VERSION 5.8 ;
BUSBITCHARS "[]" ;
DIVIDERCHAR "/" ;
UNITS
    DATABASE MICRONS 1000 ;
END UNITS

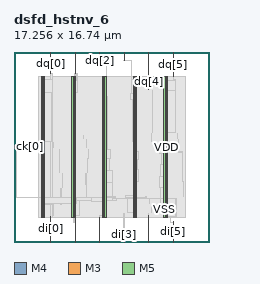
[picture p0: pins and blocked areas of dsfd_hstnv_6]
MACRO dsfd_hstnv_6
  FOREIGN dsfd_hstnv_6 0 0 ;
  CLASS BLOCK ;
  SIZE 17.256 BY 16.74 ;
  PIN ck[0]
    DIRECTION INPUT ;
    USE SIGNAL ;
    PORT
      LAYER M4 ;
        RECT  0 8.4 0.192 8.424 ;
    END
    PORT
      LAYER M4 ;
        RECT  0.156 8.4 0.275 8.424 ;
    END
  END ck[0]
  PIN di[0]
    DIRECTION INPUT ;
    USE SIGNAL ;
    PORT
      LAYER M3 ;
        RECT  3.24 0 3.258 0.144 ;
    END
    PORT
      LAYER M3 ;
        RECT  3.24 0.108 3.258 2.255 ;
    END
  END di[0]
  PIN di[1]
    DIRECTION INPUT ;
    USE SIGNAL ;
    PORT
      LAYER M5 ;
        RECT  5.376 0 5.4 0.192 ;
    END
    PORT
      LAYER M5 ;
        RECT  5.376 0.144 5.4 2.137 ;
    END
  END di[1]
  PIN di[2]
    DIRECTION INPUT ;
    USE SIGNAL ;
    PORT
      LAYER M3 ;
        RECT  7.524 0 7.542 0.144 ;
    END
    PORT
      LAYER M3 ;
        RECT  7.524 0.108 7.542 2.143 ;
    END
  END di[2]
  PIN di[3]
    DIRECTION INPUT ;
    USE SIGNAL ;
    PORT
      LAYER M5 ;
        RECT  9.696 0 9.72 0.192 ;
    END
    PORT
      LAYER M5 ;
        RECT  9.696 0.144 9.72 0.611 ;
    END
  END di[3]
  PIN di[4]
    DIRECTION INPUT ;
    USE SIGNAL ;
    PORT
      LAYER M3 ;
        RECT  11.844 0 11.862 0.144 ;
    END
    PORT
      LAYER M3 ;
        RECT  11.844 0.108 11.862 2.371 ;
    END
  END di[4]
  PIN di[5]
    DIRECTION INPUT ;
    USE SIGNAL ;
    PORT
      LAYER M5 ;
        RECT  14.016 0 14.04 0.192 ;
    END
    PORT
      LAYER M5 ;
        RECT  14.016 0.144 14.04 1.763 ;
    END
  END di[5]
  PIN dq[0]
    DIRECTION OUTPUT ;
    USE SIGNAL ;
    PORT
      LAYER M3 ;
        RECT  3.24 16.596 3.258 16.74 ;
    END
    PORT
      LAYER M3 ;
        RECT  3.24 14.864 3.258 16.62 ;
    END
  END dq[0]
  PIN dq[1]
    DIRECTION OUTPUT ;
    USE SIGNAL ;
    PORT
      LAYER M5 ;
        RECT  5.376 16.548 5.4 16.74 ;
    END
    PORT
      LAYER M5 ;
        RECT  5.376 14.867 5.4 16.592 ;
    END
  END dq[1]
  PIN dq[2]
    DIRECTION OUTPUT ;
    USE SIGNAL ;
    PORT
      LAYER M3 ;
        RECT  7.524 16.596 7.542 16.74 ;
    END
    PORT
      LAYER M3 ;
        RECT  7.524 15.989 7.542 16.62 ;
    END
  END dq[2]
  PIN dq[3]
    DIRECTION OUTPUT ;
    USE SIGNAL ;
    PORT
      LAYER M5 ;
        RECT  9.696 16.548 9.72 16.74 ;
    END
    PORT
      LAYER M5 ;
        RECT  9.696 15.973 9.72 16.592 ;
    END
  END dq[3]
  PIN dq[4]
    DIRECTION OUTPUT ;
    USE SIGNAL ;
    PORT
      LAYER M3 ;
        RECT  11.844 16.596 11.862 16.74 ;
    END
    PORT
      LAYER M3 ;
        RECT  11.844 13.441 11.862 16.62 ;
    END
  END dq[4]
  PIN dq[5]
    DIRECTION OUTPUT ;
    USE SIGNAL ;
    PORT
      LAYER M5 ;
        RECT  14.016 16.548 14.04 16.74 ;
    END
    PORT
      LAYER M5 ;
        RECT  14.016 14.603 14.04 16.592 ;
    END
  END dq[5]
  PIN VDD
    DIRECTION INOUT ;
    USE POWER ;
    PORT
      LAYER M5 ;
        RECT  13.392 2.151 13.512 14.589 ;
        RECT  10.692 2.151 10.812 14.589 ;
        RECT  7.992 2.151 8.112 14.589 ;
        RECT  5.292 2.151 5.412 14.589 ;
        RECT  2.592 2.151 2.712 14.589 ;
    END
  END VDD
  PIN VSS
    DIRECTION INOUT ;
    USE GROUND ;
    PORT
      LAYER M5 ;
        RECT  13.2 2.137 13.32 14.603 ;
        RECT  10.5 2.137 10.62 14.603 ;
        RECT  7.8 2.137 7.92 14.603 ;
        RECT  5.1 2.137 5.22 14.603 ;
        RECT  2.4 2.137 2.52 14.603 ;
    END
  END VSS
  # OT_OBS_CLOSED layer=M5 d_um=1.536 added=0
  OBS
    LAYER RVTN ;
     RECT  2.16 2.16 15.066 2.295 ;
     RECT  2.16 2.565 15.066 2.835 ;
     RECT  2.16 3.105 15.066 3.375 ;
     RECT  2.16 3.645 15.066 3.915 ;
     RECT  2.16 4.185 15.066 4.455 ;
     RECT  2.16 4.725 15.066 4.995 ;
     RECT  2.16 5.265 15.066 5.535 ;
     RECT  2.16 5.805 15.066 6.075 ;
     RECT  2.16 6.345 15.066 6.615 ;
     RECT  2.16 6.885 15.066 7.155 ;
     RECT  2.16 7.425 15.066 7.695 ;
     RECT  2.16 7.965 15.066 8.235 ;
     RECT  2.16 8.505 15.066 8.775 ;
     RECT  2.16 9.045 15.066 9.315 ;
     RECT  2.16 9.585 15.066 9.855 ;
     RECT  2.16 10.125 15.066 10.395 ;
     RECT  2.16 10.665 15.066 10.935 ;
     RECT  2.16 11.205 15.066 11.475 ;
     RECT  2.16 11.745 15.066 12.015 ;
     RECT  2.16 12.285 15.066 12.555 ;
     RECT  2.16 12.825 15.066 13.095 ;
     RECT  2.16 13.365 15.066 13.635 ;
     RECT  2.16 13.905 15.066 14.175 ;
     RECT  2.16 14.445 15.066 14.58 ;
    LAYER RVTP ;
     RECT  2.16 2.295 15.066 2.565 ;
     RECT  2.16 2.835 15.066 3.105 ;
     RECT  2.16 3.375 15.066 3.645 ;
     RECT  2.16 3.915 15.066 4.185 ;
     RECT  2.16 4.455 15.066 4.725 ;
     RECT  2.16 4.995 15.066 5.265 ;
     RECT  2.16 5.535 15.066 5.805 ;
     RECT  2.16 6.075 15.066 6.345 ;
     RECT  2.16 6.615 15.066 6.885 ;
     RECT  2.16 7.155 15.066 7.425 ;
     RECT  2.16 7.695 15.066 7.965 ;
     RECT  2.16 8.235 15.066 8.505 ;
     RECT  2.16 8.775 15.066 9.045 ;
     RECT  2.16 9.315 15.066 9.585 ;
     RECT  2.16 9.855 15.066 10.125 ;
     RECT  2.16 10.395 15.066 10.665 ;
     RECT  2.16 10.935 15.066 11.205 ;
     RECT  2.16 11.475 15.066 11.745 ;
     RECT  2.16 12.015 15.066 12.285 ;
     RECT  2.16 12.555 15.066 12.825 ;
     RECT  2.16 13.095 15.066 13.365 ;
     RECT  2.16 13.635 15.066 13.905 ;
     RECT  2.16 14.175 15.066 14.445 ;
    LAYER M1 ;
     RECT  2.16 2.151 15.066 14.589 ;
    LAYER M2 ;
     RECT  2.16 2.151 3.235 14.589 ;
     RECT  3.235 2.151 3.407 14.859 ;
     RECT  7.519 15.966 8.159 15.984 ;
     RECT  3.407 2.151 15.066 14.589 ;
    LAYER M3 ;
     RECT  5.292 1.723 5.31 2.143 ;
     RECT  13.788 1.723 13.806 2.143 ;
     RECT  13.215 2.143 13.806 2.191 ;
     RECT  13.215 2.191 14.274 2.255 ;
     RECT  7.524 2.143 7.905 2.291 ;
     RECT  5.115 2.143 5.31 2.371 ;
     RECT  2.415 2.143 2.505 2.413 ;
     RECT  7.776 2.291 7.905 2.413 ;
     RECT  10.515 2.143 10.605 2.413 ;
     RECT  3.456 2.371 3.474 2.489 ;
     RECT  9.684 0.571 9.702 2.489 ;
     RECT  11.808 2.371 11.862 2.489 ;
     RECT  10.515 2.413 10.797 2.641 ;
     RECT  3.492 2.641 3.51 3.299 ;
     RECT  12.132 2.641 12.15 3.299 ;
     RECT  13.215 2.255 13.497 3.307 ;
     RECT  2.415 2.413 2.697 3.343 ;
     RECT  2.415 3.343 3.33 3.437 ;
     RECT  7.776 2.413 8.097 3.547 ;
     RECT  5.115 2.371 5.742 3.643 ;
     RECT  6.84 3.547 6.858 3.643 ;
     RECT  7.632 3.547 8.097 3.643 ;
     RECT  5.115 3.643 8.097 3.773 ;
     RECT  10.008 2.641 10.797 3.835 ;
     RECT  11.952 3.415 11.97 3.835 ;
     RECT  12.924 3.307 13.497 3.835 ;
     RECT  14.256 2.255 14.274 3.835 ;
     RECT  12.924 3.835 14.274 3.839 ;
     RECT  10.008 3.835 11.97 3.869 ;
     RECT  5.115 3.773 6.426 3.875 ;
     RECT  7.632 3.773 8.097 3.875 ;
     RECT  10.008 3.869 11.646 3.875 ;
     RECT  12.924 3.839 13.986 3.875 ;
     RECT  7.815 3.875 8.097 3.883 ;
     RECT  8.964 3.643 8.982 3.883 ;
     RECT  10.008 3.875 10.797 3.931 ;
     RECT  11.628 3.875 11.646 3.965 ;
     RECT  7.815 3.883 8.982 4.019 ;
     RECT  9.828 3.931 10.797 4.109 ;
     RECT  4.14 3.307 4.158 4.685 ;
     RECT  12.924 3.875 13.497 4.801 ;
     RECT  6.408 3.875 6.426 4.955 ;
     RECT  7.815 4.019 8.694 5.225 ;
     RECT  14.904 3.991 14.922 5.333 ;
     RECT  10.515 4.109 10.797 5.341 ;
     RECT  12.816 4.801 13.497 5.765 ;
     RECT  4.248 4.801 4.266 6.035 ;
     RECT  6.336 5.071 6.354 6.035 ;
     RECT  7.815 5.225 8.658 6.305 ;
     RECT  10.515 5.341 10.926 6.413 ;
     RECT  12.888 5.765 13.497 6.845 ;
     RECT  4.032 6.151 4.05 7.222 ;
     RECT  3.996 7.222 4.05 7.223 ;
     RECT  10.515 6.413 10.854 7.231 ;
     RECT  6.444 6.151 6.462 7.321 ;
     RECT  7.815 6.305 8.406 7.321 ;
     RECT  6.444 7.321 6.606 7.385 ;
     RECT  12.996 6.845 13.497 7.771 ;
     RECT  14.832 5.341 14.85 7.861 ;
     RECT  10.515 7.231 10.962 7.961 ;
     RECT  14.472 7.861 14.85 7.961 ;
     RECT  3.996 7.223 4.014 8.159 ;
     RECT  6.588 7.385 6.606 8.159 ;
     RECT  7.815 7.321 8.478 8.159 ;
     RECT  3.492 8.311 3.51 8.735 ;
     RECT  12.816 7.771 13.497 8.735 ;
     RECT  2.415 3.437 2.697 8.851 ;
     RECT  10.515 7.961 10.797 8.851 ;
     RECT  6.372 8.311 6.39 9.005 ;
     RECT  10.404 8.851 10.797 9.005 ;
     RECT  14.472 7.961 14.49 9.005 ;
     RECT  6.12 9.085 6.138 9.383 ;
     RECT  5.115 3.875 5.397 9.391 ;
     RECT  12.096 8.851 12.114 9.545 ;
     RECT  14.4 9.121 14.418 9.581 ;
     RECT  13.215 8.735 13.497 9.661 ;
     RECT  10.476 9.005 10.797 12.559 ;
     RECT  7.815 8.159 8.262 12.785 ;
     RECT  10.26 12.559 10.797 13.055 ;
     RECT  2.415 8.851 3.33 13.171 ;
     RECT  5.115 9.391 5.454 13.171 ;
     RECT  12.168 9.661 12.186 13.325 ;
     RECT  13.215 9.661 14.202 13.325 ;
     RECT  5.115 13.171 5.562 14.237 ;
     RECT  14.22 13.441 14.238 14.285 ;
     RECT  2.415 13.171 3.402 14.327 ;
     RECT  5.115 14.237 5.397 14.327 ;
     RECT  10.332 13.055 10.797 14.327 ;
     RECT  13.215 13.325 13.497 14.327 ;
     RECT  2.415 14.327 2.505 14.597 ;
     RECT  5.115 14.327 5.205 14.597 ;
     RECT  7.815 12.785 8.154 14.597 ;
     RECT  10.332 14.327 10.605 14.597 ;
     RECT  13.215 14.327 13.305 14.597 ;
     RECT  3.24 14.327 3.402 14.864 ;
     RECT  8.136 14.597 8.154 15.961 ;
     RECT  7.524 15.961 8.154 15.989 ;
     RECT  10.332 14.597 10.35 16.013 ;
    LAYER M4 ;
     RECT  0.229 3.888 2.408 3.912 ;
     RECT  2.408 2.148 2.512 14.592 ;
     RECT  2.512 2.418 2.704 14.322 ;
     RECT  2.704 3.408 5.108 3.912 ;
     RECT  5.108 2.148 5.281 14.592 ;
     RECT  5.281 1.728 5.365 14.592 ;
     RECT  5.365 1.728 5.404 14.856 ;
     RECT  5.404 1.728 5.411 1.752 ;
     RECT  5.404 3.408 5.501 3.912 ;
     RECT  5.404 14.208 5.555 14.856 ;
     RECT  5.555 14.208 5.573 14.232 ;
     RECT  5.501 3.648 6.829 3.912 ;
     RECT  6.829 3.552 7.808 3.912 ;
     RECT  7.808 2.148 7.912 14.592 ;
     RECT  7.912 2.418 8.104 14.322 ;
     RECT  8.104 3.648 8.669 3.912 ;
     RECT  8.669 3.648 8.993 3.864 ;
     RECT  9.673 0.576 9.757 0.6 ;
     RECT  8.993 3.84 9.817 3.864 ;
     RECT  9.685 15.984 10.361 16.008 ;
     RECT  9.817 3.84 10.508 3.96 ;
     RECT  10.508 2.148 10.612 14.592 ;
     RECT  10.612 2.418 10.804 14.322 ;
     RECT  10.804 3.84 11.657 3.96 ;
     RECT  11.657 3.84 13.208 3.864 ;
     RECT  13.208 2.148 13.312 14.592 ;
     RECT  13.312 2.148 13.504 14.322 ;
     RECT  13.504 3.84 13.997 3.864 ;
     RECT  13.777 1.728 14.051 1.752 ;
     RECT  13.504 14.256 14.249 14.28 ;
    LAYER M5 ;
     RECT  2.4 2.137 2.52 2.151 ;
     RECT  5.1 2.137 5.4 2.151 ;
     RECT  7.8 2.137 7.92 2.151 ;
     RECT  10.5 2.137 10.62 2.151 ;
     RECT  0.24 3.877 0.264 8.435 ;
     RECT  5.1 2.151 5.412 14.197 ;
     RECT  13.2 2.137 13.512 14.245 ;
     RECT  2.4 2.151 2.712 14.589 ;
     RECT  7.8 2.151 8.112 14.589 ;
     RECT  10.5 2.151 10.812 14.589 ;
     RECT  2.4 14.589 2.52 14.603 ;
     RECT  5.1 14.197 5.544 14.603 ;
     RECT  7.8 14.589 7.92 14.603 ;
     RECT  10.5 14.589 10.62 14.603 ;
     RECT  13.2 14.245 14.04 14.603 ;
     RECT  5.376 14.603 5.544 14.867 ;
  END
END dsfd_hstnv_6
END LIBRARY
